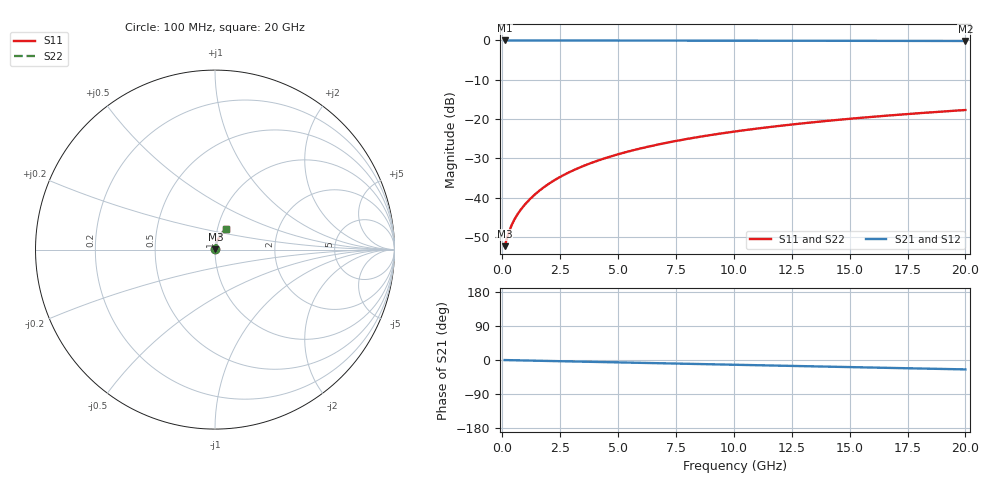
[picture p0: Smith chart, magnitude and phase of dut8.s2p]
! Touchstone file exported from HFSS 2026.1.0
!  File:  C:/ffzhzh/LocalFiles/Ansys_Project_Files/temp_test_TMRDL_8_1782906923_46784.aedt
!  Generated:  07:56:35 PM Jul  1, 2026
!  Design:  TMRDL
!  Project:  temp_test_TMRDL_8_1782906923_46784
! Variables:
!  h_bsmrdl = 2um
!  h_ox = 20um
!  h_rdl = 5um
!  h_sub = 80um
!  h_tmrdl = 2.58um
!  h_tsv = 80um
!  h_via = 3um
!  l_bsmrdl = 300um
!  l_sub = 795.07um
!  l_tmrdl = 395.07um
!  m_sub = 200um
!  pitch = 39.89um
!  r_tsv = 6um
!  s_tmrdl = 10um
!  w_bsmrdl = 18um
!  w_sub = 500um
!  w_tmrdl = 29.45um
!  x_tsv_center1 = 409.795um
!  x_tsv_center2 = 727.795um
!  x_tsv_center3 = 1152.315um
!  x_tsv_center4 = 1470.315um
!  x_tsv_center5 = 1894.835um
!  x_tsv_center6 = 2212.835um
# GHz S MA R 50.000000
! Terminal data exported
! Port[1] = TM_RDL1_1_T1
! Port[2] = TM_RDL1_1_T2
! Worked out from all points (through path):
!   200 points, 100 MHz to 20 GHz, reference 50 ohm
!   highest |S21| = -0.02 dB at 100 MHz (marker M1); lowest = -0.2 dB at 20 GHz (marker M2)
!   group delay of S21, straight-line fit = 3.45 ps
!   lowest |S11| = -52.3 dB at 100 MHz (marker M3), VSWR 1.00, Z = 50.2 + j0.0983 ohm
!   |S11| at or under -10 dB: start of sweep to end of sweep
!   |S22| runs from -52.3 to -17.7 dB; largest |S21 - S12| = 4.8e-15
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0.1  0.002423 23.8  0.9978 -0.1  0.9978 -0.1  0.002423 23.8
! Gamma 0 0 0 0
! Port Impedance 50 0 50 0
0.3  0.003745 46.9  0.9975 -0.4  0.9975 -0.4  0.003745 46.9
0.4  0.004451 51.9  0.9973 -0.5  0.9973 -0.5  0.004451 51.9
0.5  0.00513 55.3  0.9971 -0.7  0.9971 -0.7  0.00513 55.3
0.6  0.005786 58.0  0.997 -0.8  0.997 -0.8  0.005786 58.0
0.8  0.007068 62.2  0.9968 -1.0  0.9968 -1.0  0.007068 62.2
1  0.008347 65.4  0.9967 -1.3  0.9967 -1.3  0.008347 65.4
1.2  0.009642 67.9  0.9966 -1.5  0.9966 -1.5  0.009642 67.9
1.7  0.01296 72.1  0.9964 -2.2  0.9964 -2.2  0.01296 72.1
2.2  0.01635 74.4  0.9963 -2.8  0.9963 -2.8  0.01635 74.4
2.8  0.02047 75.9  0.9961 -3.6  0.9961 -3.6  0.02047 75.9
3.5  0.02531 76.7  0.9958 -4.4  0.9958 -4.4  0.02531 76.7
4.2  0.03015 76.9  0.9955 -5.3  0.9955 -5.3  0.03015 76.9
5  0.03567 76.8  0.9951 -6.3  0.9951 -6.3  0.03567 76.8
5.9  0.04184 76.3  0.9946 -7.5  0.9946 -7.5  0.04184 76.3
6.8  0.04796 75.6  0.994 -8.6  0.994 -8.6  0.04796 75.6
8.3  0.05802 74.2  0.993 -10.5  0.993 -10.5  0.05802 74.3
10.1  0.06986 72.4  0.9916 -12.7  0.9916 -12.7  0.06986 72.4
11.7  0.08016 70.6  0.9903 -14.7  0.9903 -14.7  0.08017 70.7
13.4  0.09089 68.7  0.9888 -16.8  0.9888 -16.8  0.09089 68.8
16.7  0.111 65.0  0.9857 -20.8  0.9857 -20.8  0.111 65.0
20  0.1303 61.3  0.9825 -24.8  0.9825 -24.8  0.1303 61.3
